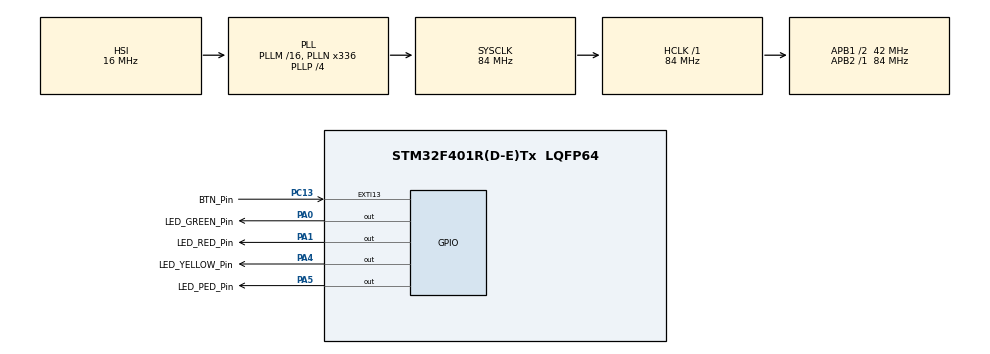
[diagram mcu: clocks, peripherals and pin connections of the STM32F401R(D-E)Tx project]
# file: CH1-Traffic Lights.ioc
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Mcu.Family=STM32F4
Mcu.Name=STM32F401R(D-E)Tx
Mcu.Package=LQFP64
NVIC.PriorityGroup=NVIC_PRIORITYGROUP_0
PA0-WKUP.GPIO_Label=LED_GREEN_Pin
PA0-WKUP.Signal=GPIO_Output
PA1.GPIO_Label=LED_RED_Pin
PA1.Signal=GPIO_Output
PA13.GPIO_Label=TMS
PA13.Signal=SYS_JTMS-SWDIO
PA14.GPIO_Label=TCK
PA14.Signal=SYS_JTCK-SWCLK
PA2.GPIO_Label=USART_TX
PA2.GPIO_Mode=GPIO_MODE_AF_PP
PA2.GPIO_PuPd=GPIO_NOPULL
PA2.GPIO_Speed=GPIO_SPEED_FREQ_LOW
PA2.Signal=USART2_TX
PA3.GPIO_Label=USART_RX
PA3.GPIO_Mode=GPIO_MODE_AF_PP
PA3.GPIO_PuPd=GPIO_NOPULL
PA3.GPIO_Speed=GPIO_SPEED_FREQ_LOW
PA3.Signal=USART2_RX
PA4.GPIO_Label=LED_YELLOW_Pin
PA4.Signal=GPIO_Output
PA5.GPIO_Label=LED_PED_Pin
PA5.GPIO_Mode=GPIO_MODE_OUTPUT_PP
PA5.GPIO_PuPd=GPIO_NOPULL
PA5.GPIO_Speed=GPIO_SPEED_FREQ_LOW
PA5.Signal=GPIO_Output
PB3.GPIO_Label=SWO
PB3.Signal=SYS_JTDO-SWO
PC13-ANTI_TAMP.GPIO_Label=BTN_Pin
PC13-ANTI_TAMP.GPIO_ModeDefaultEXTI=GPIO_MODE_IT_FALLING
PC13-ANTI_TAMP.GPIO_PuPd=GPIO_NOPULL
PC13-ANTI_TAMP.Signal=GPXTI13
PC14-OSC32_IN.Signal=RCC_OSC32_IN
PC15-OSC32_OUT.Signal=RCC_OSC32_OUT
PH0\ -\ OSC_IN.Signal=RCC_OSC_IN
PH1\ -\ OSC_OUT.Signal=RCC_OSC_OUT
ProjectManager.HeapSize=0x200
ProjectManager.StackSize=0x400
ProjectManager.TargetToolchain=STM32CubeIDE
RCC.AHBFreq_Value=84000000
RCC.APB1CLKDivider=RCC_HCLK_DIV2
RCC.APB1Freq_Value=42000000
RCC.APB1TimFreq_Value=84000000
RCC.APB2Freq_Value=84000000
RCC.APB2TimFreq_Value=84000000
RCC.CortexFreq_Value=84000000
RCC.HCLKFreq_Value=84000000
RCC.HSE_VALUE=8000000
RCC.HSI_VALUE=16000000
RCC.LSE_VALUE=32768
RCC.PLLN=336
RCC.PLLP=RCC_PLLP_DIV4
RCC.PLLQ=7
RCC.SYSCLKFreq_VALUE=84000000
RCC.SYSCLKSource=RCC_SYSCLKSOURCE_PLLCLK
RCC.VCOOutputFreq_Value=336000000
board=NUCLEO-F401RE

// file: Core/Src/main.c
/* USER CODE BEGIN Header */
/**
  ******************************************************************************
  * @file           : main.c
  * @brief          : Main program body
  ******************************************************************************
  * @attention
  *
  * Copyright (c) 2026 STMicroelectronics.
  * All rights reserved.
  *
  * This software is licensed under terms that can be found in the LICENSE file
  * in the root directory of this software component.
  * If no LICENSE file comes with this software, it is provided AS-IS.
  *
  ******************************************************************************
  */
/* USER CODE END Header */
#include "main.h"

/* USER CODE BEGIN Includes */
#include "stdint.h"
/* USER CODE END Includes */

void SystemClock_Config(void);
static void MX_GPIO_Init(void);

/* USER CODE BEGIN 0 */

/*----------------------------TRAFFIC LIGHT STATES------------------------------*/
typedef enum {
	ST_RED,
	ST_RED_YELLOW,
	ST_GREEN,
	ST_YELLOW,
	ST_PEDESTRIAN
}traffic_state_t;

/*----------------------------TIMING CONSTANTS------------------------------*/
#define T_RED 2000U
#define T_RED_YELLOW 500U
#define T_GREEN 3000U
#define T_YELLOW 1000U
#define T_PED 5000U

/*-----------------------------TRAFFIC LIGHT STATE--------------------------*/
static traffic_state_t tf_state = ST_RED;
static uint32_t tf_state_ms = 0;
static uint8_t ped_req = 0;

/*----------------------------BUTTON DEBOUNCING------------------------------*/
typedef enum {
	BTN_RELEASED = 0,
	BTN_DEBOUNCE_PRESS,
	BTN_PRESSED,
	BTN_DEBOUNCE_RELEASE
}btn_state_t;

static btn_state_t btn_state = BTN_RELEASED;
static uint16_t btn_counter = 0;
#define BTN_DEBOUNCE_SAMPLES 20U

/*----------------------------OUTPUT HELPERS------------------------------*/
static void tf_set_outputs(traffic_state_t s){
	//RED is on in RED, RED_YELLOW and PEDESTRIAN phases
	HAL_GPIO_WritePin(LED_RED_GPIO_Port, LED_RED_Pin, (s==ST_RED || s==ST_RED_YELLOW || s==ST_PEDESTRIAN) ? GPIO_PIN_SET : GPIO_PIN_RESET);

	//Yellow is on in RED_YELLOW and YELLOW phases
	HAL_GPIO_WritePin(LED_YELLOW_GPIO_Port, LED_YELLOW_Pin, (s==ST_YELLOW || s==ST_RED_YELLOW) ? GPIO_PIN_SET : GPIO_PIN_RESET);

	//Green only on in GREEN phase
	HAL_GPIO_WritePin(LED_GREEN_GPIO_Port, LED_GREEN_Pin, s==ST_GREEN ? GPIO_PIN_SET : GPIO_PIN_RESET);

	//Pedestian LED on only in PEDESTRIAN phase
	HAL_GPIO_WritePin(LED_PED_GPIO_Port, LED_PED_Pin, s==ST_PEDESTRIAN ? GPIO_PIN_SET : GPIO_PIN_RESET);
}

static void tf_enter(traffic_state_t next, uint32_t now){
	tf_state = next;
	tf_state_ms = now;
	tf_set_outputs(next);
}

/*----------------------------TRAFFIC LIGHT FSM------------------------------*/

static void traffic_tick(uint32_t now){
	uint32_t elapsed = now - tf_state_ms;

	switch(tf_state){
	case ST_RED:
		if(elapsed>=T_RED){
			tf_enter(ST_RED_YELLOW, now);
		}
		break;

	case ST_RED_YELLOW:
		if(elapsed>=T_RED_YELLOW){
			tf_enter(ST_GREEN, now);
		}
		break;

	case ST_GREEN:
		if(elapsed>=T_GREEN){
			tf_enter(ST_YELLOW, now);
		}
		break;

	case ST_YELLOW:
		if(elapsed>=ST_YELLOW){
			if(ped_req){
				ped_req = 0;
				tf_enter(ST_PEDESTRIAN, now);
			}
			else{
				tf_enter(ST_RED, now);
			}
		}
		break;

	case ST_PEDESTRIAN:
		if(elapsed>=T_PED){
			tf_enter(ST_RED, now);
		}
		break;
	}
}

/*----------------------------BUTTON DEBOUNCER FSM------------------------------*/

static void button_tick(void){
	//Remember, onboard button active low. 0 when pressed, 1 when released
	uint8_t raw_pressed = (HAL_GPIO_ReadPin(BTN_GPIO_Port, BTN_Pin)==GPIO_PIN_RESET) ? 1U : 0U;

	switch(btn_state){
	case BTN_RELEASED:
		if(raw_pressed){
			btn_state = BTN_DEBOUNCE_PRESS;
			btn_counter = 0;
		}
		break;

	case BTN_DEBOUNCE_PRESS:
		if(!raw_pressed){
			btn_state = BTN_RELEASED;
		}
		else if (++btn_counter >= BTN_DEBOUNCE_SAMPLES){
			btn_state = BTN_PRESSED;
			ped_req = 1;
		}
		break;

	case BTN_PRESSED:
		if(!raw_pressed){
			btn_state = BTN_DEBOUNCE_RELEASE;
			btn_counter = 0;
		}
		break;

	case BTN_DEBOUNCE_RELEASE:
		if(raw_pressed){
			btn_state = BTN_PRESSED;
		}
		else if (++btn_counter>= BTN_DEBOUNCE_SAMPLES){
			btn_state = BTN_RELEASED;
		}
		break;
	}
}

/* USER CODE END 0 */

int main(void)
{

  /* MCU Configuration--------------------------------------------------------*/

  /* Reset of all peripherals, Initializes the Flash interface and the Systick. */
  HAL_Init();

  /* Configure the system clock */
  SystemClock_Config();

  /* Initialize all configured peripherals */
  MX_GPIO_Init();

  /* Infinite loop */
  while (1)
  {

    /* USER CODE BEGIN 3 */
	  uint32_t now = HAL_GetTick();
	  button_tick();
	  traffic_tick(now);
  }
  /* USER CODE END 3 */
}

void SystemClock_Config(void)
{
  RCC_OscInitTypeDef RCC_OscInitStruct = {0};
  RCC_ClkInitTypeDef RCC_ClkInitStruct = {0};

  /** Configure the main internal regulator output voltage
  */
  __HAL_RCC_PWR_CLK_ENABLE();
  __HAL_PWR_VOLTAGESCALING_CONFIG(PWR_REGULATOR_VOLTAGE_SCALE2);

  /** Initializes the RCC Oscillators according to the specified parameters
  * in the RCC_OscInitTypeDef structure.
  */
  RCC_OscInitStruct.OscillatorType = RCC_OSCILLATORTYPE_HSI;
  RCC_OscInitStruct.HSIState = RCC_HSI_ON;
  RCC_OscInitStruct.HSICalibrationValue = RCC_HSICALIBRATION_DEFAULT;
  RCC_OscInitStruct.PLL.PLLState = RCC_PLL_ON;
  RCC_OscInitStruct.PLL.PLLSource = RCC_PLLSOURCE_HSI;
  RCC_OscInitStruct.PLL.PLLM = 16;
  RCC_OscInitStruct.PLL.PLLN = 336;
  RCC_OscInitStruct.PLL.PLLP = RCC_PLLP_DIV4;
  RCC_OscInitStruct.PLL.PLLQ = 7;
  if (HAL_RCC_OscConfig(&RCC_OscInitStruct) != HAL_OK)
  {
    Error_Handler();
  }

  /** Initializes the CPU, AHB and APB buses clocks
  */
  RCC_ClkInitStruct.ClockType = RCC_CLOCKTYPE_HCLK|RCC_CLOCKTYPE_SYSCLK
                              |RCC_CLOCKTYPE_PCLK1|RCC_CLOCKTYPE_PCLK2;
  RCC_ClkInitStruct.SYSCLKSource = RCC_SYSCLKSOURCE_PLLCLK;
  RCC_ClkInitStruct.AHBCLKDivider = RCC_SYSCLK_DIV1;
  RCC_ClkInitStruct.APB1CLKDivider = RCC_HCLK_DIV2;
  RCC_ClkInitStruct.APB2CLKDivider = RCC_HCLK_DIV1;

  if (HAL_RCC_ClockConfig(&RCC_ClkInitStruct, FLASH_LATENCY_2) != HAL_OK)
  {
    Error_Handler();
  }
}

static void MX_GPIO_Init(void)
{
  GPIO_InitTypeDef GPIO_InitStruct = {0};

  /* GPIO Ports Clock Enable */
  __HAL_RCC_GPIOC_CLK_ENABLE();
  __HAL_RCC_GPIOH_CLK_ENABLE();
  __HAL_RCC_GPIOA_CLK_ENABLE();
  __HAL_RCC_GPIOB_CLK_ENABLE();

  /*Configure GPIO pin Output Level */
  HAL_GPIO_WritePin(GPIOA, LED_GREEN_Pin|LED_RED_Pin|LED_YELLOW_Pin|LED_PED_Pin, GPIO_PIN_RESET);

  /*Configure GPIO pin : BTN_Pin_Pin */
  GPIO_InitStruct.Pin = BTN_Pin;
  GPIO_InitStruct.Mode = GPIO_MODE_IT_FALLING;
  GPIO_InitStruct.Pull = GPIO_NOPULL;
  HAL_GPIO_Init(BTN_GPIO_Port, &GPIO_InitStruct);

  /*Configure GPIO pins : LED_GREEN_Pin_Pin LED_RED_Pin_Pin LED_YELLOW_Pin_Pin LED_PED_Pin_Pin */
  GPIO_InitStruct.Pin = LED_GREEN_Pin|LED_RED_Pin|LED_YELLOW_Pin|LED_PED_Pin;
  GPIO_InitStruct.Mode = GPIO_MODE_OUTPUT_PP;
  GPIO_InitStruct.Pull = GPIO_NOPULL;
  GPIO_InitStruct.Speed = GPIO_SPEED_FREQ_LOW;
  HAL_GPIO_Init(GPIOA, &GPIO_InitStruct);

  /*Configure GPIO pins : USART_TX_Pin USART_RX_Pin */
  GPIO_InitStruct.Pin = USART_TX_Pin|USART_RX_Pin;
  GPIO_InitStruct.Mode = GPIO_MODE_AF_PP;
  GPIO_InitStruct.Pull = GPIO_NOPULL;
  GPIO_InitStruct.Speed = GPIO_SPEED_FREQ_LOW;
  GPIO_InitStruct.Alternate = GPIO_AF7_USART2;
  HAL_GPIO_Init(GPIOA, &GPIO_InitStruct);

}

void Error_Handler(void)
{
  __disable_irq();
  while (1)
  {
  }
}
